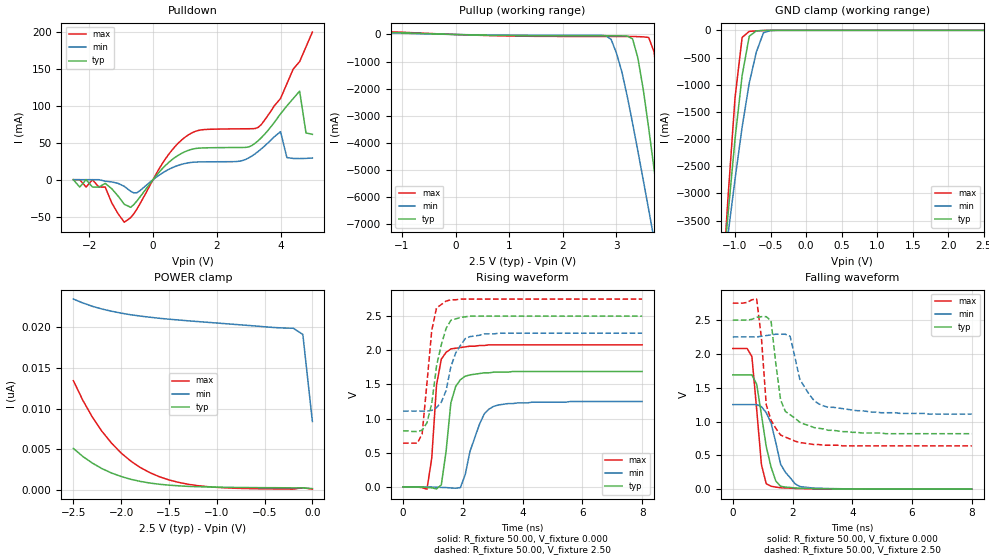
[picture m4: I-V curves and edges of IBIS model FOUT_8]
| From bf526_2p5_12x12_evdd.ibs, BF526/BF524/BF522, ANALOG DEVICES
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|   Model prw0408swcdg_3v_25
[Model]   FOUT_8
Model_type   I/O
Polarity   Non-Inverting
Enable   Active-Low
Vinl =   0.70V
Vinh =   1.70V
Vmeas =   1.20V
Cref =  50.00pF
Rref =   1.00M
Vref =  0.000V
C_comp   4.87pF   4.38pF   5.35pF
[Temperature Range]   25.00   0.12k   -40.00
[Voltage Range]   2.50V   2.25V   2.75V
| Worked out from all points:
|   slope of the pulldown table from 0 to 0.375 V, typ, clamps not added: 20.2 ohm
|   slope of the pullup table from 0 to 0.375 V, typ, clamps not added: 20.2 ohm
|   GND clamp passes 1 mA (typ) near -0.53 V on its own axis
|   rising waveform, R_fixture 50.00, V_fixture 0.000: 20-80 % time 301ps typ, 532ps min, 235ps max; typ from 0 V to 1.69 V
|   rising waveform, R_fixture 50.00, V_fixture 2.50: 20-80 % time 413ps typ, 478ps min, 277ps max; typ from 0.82 V to 2.5 V
|   falling waveform, R_fixture 50.00, V_fixture 0.000: 20-80 % time 405ps typ, 501ps min, 248ps max; typ from 1.69 V to 0 V
|   falling waveform, R_fixture 50.00, V_fixture 2.50: 20-80 % time 392ps typ, 627ps min, 318ps max; typ from 2.5 V to 0.82 V
[Pulldown]
| voltage   I(typ)   I(min)   I(max)
-2.5V     0A         0A         0A
-1.5V     -5mA       -2mA       -10mA
-900mV    -33.4mA    -9mA       -57.6mA
-500mV    -28.54mA   -17.58mA   -39.44mA
1V        37.88mA    21.94mA    57.43mA
3V        44.3mA     29.45mA    69.02mA
3.4V      56.95mA    41.79mA    74.82mA
4V        89.19mA    65.09mA    110mA
4.2V      100mA      29.92mA    130mA
4.6V      120mA      28.6mA     160mA
4.8V      63.36mA    28.84mA    180mA
5V        61.44mA    29.36mA    200mA
[Pullup]
| voltage   I(typ)   I(min)   I(max)
-2.5V     14.15mA    2.47mA     45.09mA
2.8V      -46.96mA   -42.82mA   -72.11mA
2.9V      -47.06mA   -180mA     -72.23mA
3V        -47.56mA   -690mA     -72.33mA
3.3V      -160mA     -3.28A     -74.26mA
3.4V      -880mA     -4.32A     -79.19mA
3.6V      -3.46A     -6.47A     -110mA
3.7V      -4.96A     -7.56A     -640mA
3.8V      -6.5A      -8.65A     -2.2A
4V        -9.62A     -10.85A    -6.34A
4.2V      -12.77A    -13.07A    -10.72A
5V        -25.49A    -21.97A    -28.57A
[GND_clamp]
| voltage   I(typ)   I(min)   I(max)
-2.5V     -25.44A    -19.16A    -34.1A
-1.2V     -4.91A     -4.82A     -5.19A
-1.1V     -3.41A     -3.77A     -3.1A
-1V       -2A        -2.74A     -1.24A
-900mV    -830mA     -1.78A     -130mA
-800mV    -110mA     -970mA     -19.37mA
-700mV    -10.09mA   -400mA     -9.85mA
-600mV    -2.6mA     -44.25mA   -3.52mA
-500mV    -460uA     -4.5mA     -550uA
2.5V      210pA      19.84nA    120pA
[POWER_clamp]
| voltage   I(typ)   I(min)   I(max)
-2.5V     5.13nA     23.39nA    13.41nA
-2.4V     4.13nA     22.91nA    10.99nA
-2.3V     3.32nA     22.5nA     8.93nA
-2.1V     2.11nA     21.9nA     5.76nA
-1.9V     1.35nA     21.47nA    3.58nA
-1.7V     890pA      21.17nA    2.16nA
-1.5V     630pA      20.93nA    1.27nA
-1.2V     440pA      20.64nA    570pA
-800mV    350pA      20.28nA    250pA
-200mV    300pA      19.82nA    150pA
-100mV    300pA      19.07nA    310pA
0V        210pA      8.42nA     140pA
[Ramp]
| variable   typ   min   max
dV/dt_r   1.02/0.30n   0.75/0.50n   1.25/0.19n
dV/dt_f   1.01/0.40n   0.68/0.65n   1.27/0.26n
R_load = 50.00
[Rising Waveform]
R_fixture = 50.00
V_fixture = 0.000
V_fixture_min = 0.000
V_fixture_max = 0.000
L_fixture = 0.000H
C_fixture = 0.000F
| time   V(typ)   V(min)   V(max)
0s        0V         0V         0V
800ps     -9.11mV    -780uV     -33.44mV
960ps     -13.22mV   -2.26mV    420mV
1.12ns    -30.54mV   -4.75mV    1.49V
1.28ns    28.95mV    -7.63mV    1.87V
1.6ns     1.23V      -15.62mV   2.02V
1.92ns    1.57V      -10.23mV   2.04V
2.56ns    1.66V      920mV      2.07V
3.04ns    1.68V      1.18V      2.08V
8ns       1.69V      1.25V      2.08V
[Rising Waveform]
R_fixture = 50.00
V_fixture = 2.50
V_fixture_min = 2.25
V_fixture_max = 2.75
L_fixture = 0.000H
C_fixture = 0.000F
| time   V(typ)   V(min)   V(max)
0s        820mV      1.11V      640mV
480ps     810mV      1.11V      640mV
640ps     830mV      1.11V      780mV
800ps     940mV      1.11V      1.52V
960ps     1.22V      1.12V      2.29V
1.12ns    1.77V      1.16V      2.62V
1.44ns    2.32V      1.41V      2.72V
1.76ns    2.46V      1.96V      2.74V
2.24ns    2.5V       2.2V       2.75V
8ns       2.5V       2.25V      2.75V
[Falling Waveform]
R_fixture = 50.00
V_fixture = 0.000
V_fixture_min = 0.000
V_fixture_max = 0.000
L_fixture = 0.000H
C_fixture = 0.000F
| time   V(typ)   V(min)   V(max)
0s        1.69V      1.25V      2.08V
480ps     1.69V      1.25V      2.08V
640ps     1.69V      1.25V      1.96V
800ps     1.55V      1.25V      1.18V
960ps     1.1V       1.22V      360mV
1.12ns    630mV      1.13V      79.27mV
1.44ns    120mV      690mV      30.31mV
1.6ns     43.21mV    370mV      21.03mV
2.24ns    14.24mV    39.02mV    8.3mV
8ns       42.72uV    120uV      -8.09uV
[Falling Waveform]
R_fixture = 50.00
V_fixture = 2.50
V_fixture_min = 2.25
V_fixture_max = 2.75
L_fixture = 0.000H
C_fixture = 0.000F
| time   V(typ)   V(min)   V(max)
0s        2.5V       2.25V      2.75V
800ps     2.54V      2.25V      2.81V
960ps     2.55V      2.26V      2.23V
1.12ns    2.55V      2.27V      1.25V
1.28ns    2.49V      2.28V      1.02V
1.6ns     1.32V      2.29V      800mV
1.92ns    1.1V       2.26V      740mV
2.24ns    990mV      1.63V      690mV
3.04ns    890mV      1.23V      650mV
8ns       820mV      1.11V      640mV
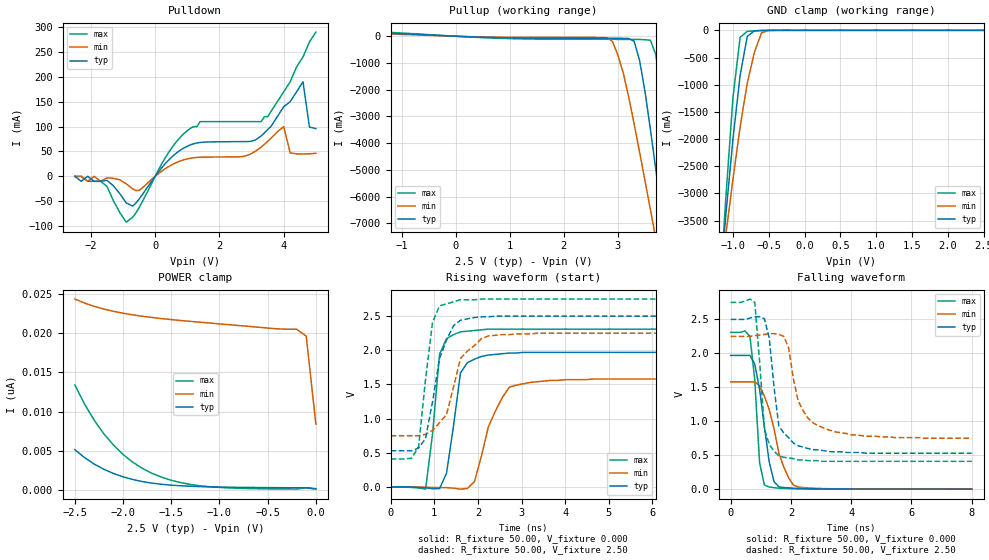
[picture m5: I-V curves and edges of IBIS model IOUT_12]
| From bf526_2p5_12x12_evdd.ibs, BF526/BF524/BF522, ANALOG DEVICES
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|   Model prw0812swcdg_25
[Model]   IOUT_12
Model_type   I/O
Polarity   Non-Inverting
Enable   Active-Low
Vinl =   0.70V
Vinh =   1.70V
Vmeas =   1.20V
Cref =  50.00pF
Rref =   1.00M
Vref =  0.000V
C_comp   4.63pF   4.16pF   5.09pF
[Temperature Range]   25.00   0.12k   -40.00
[Voltage Range]   2.50V   2.25V   2.75V
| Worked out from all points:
|   slope of the pulldown table from 0 to 0.375 V, typ, clamps not added: 12.6 ohm
|   slope of the pullup table from 0 to 0.375 V, typ, clamps not added: 12.7 ohm
|   GND clamp passes 1 mA (typ) near -0.53 V on its own axis
|   rising waveform, R_fixture 50.00, V_fixture 0.000: 20-80 % time 256ps typ, 501ps min, 210ps max; typ from 0 V to 1.97 V
|   rising waveform, R_fixture 50.00, V_fixture 2.50: 20-80 % time 391ps typ, 435ps min, 249ps max; typ from 0.53 V to 2.5 V
|   falling waveform, R_fixture 50.00, V_fixture 0.000: 20-80 % time 369ps typ, 569ps min, 210ps max; typ from 1.97 V to 0 V
|   falling waveform, R_fixture 50.00, V_fixture 2.50: 20-80 % time 302ps typ, 591ps min, 242ps max; typ from 2.5 V to 0.53 V
[Pulldown]
| voltage   I(typ)   I(min)   I(max)
-2.5V     0A         0A         0A
-1.5V     -8mA       -3mA       -20mA
-900mV    -53.4mA    -15mA      -92.2mA
-500mV    -45.67mA   -28.14mA   -63.1mA
900mV     57.24mA    33.39mA    86.24mA
1.4V      68.13mA    38.37mA    110mA
3.3V      81.45mA    59.05mA    110mA
4V        140mA      100mA      170mA
4.2V      150mA      47.04mA    190mA
4.6V      190mA      44.93mA    240mA
4.8V      99.01mA    45.32mA    270mA
5V        95.95mA    46.14mA    290mA
[Pullup]
| voltage   I(typ)   I(min)   I(max)
-2.5V     20.28mA    3.12mA     63.15mA
2.8V      -74.78mA   -59.76mA   -110mA
2.9V      -74.93mA   -200mA     -110mA
3V        -75.48mA   -710mA     -120mA
3.3V      -190mA     -3.29A     -120mA
3.4V      -910mA     -4.34A     -120mA
3.6V      -3.49A     -6.49A     -150mA
3.7V      -4.99A     -7.58A     -690mA
3.8V      -6.53A     -8.67A     -2.24A
4V        -9.65A     -10.87A    -6.38A
4.2V      -12.8A     -13.09A    -10.76A
5V        -25.52A    -21.99A    -28.62A
[GND_clamp]
| voltage   I(typ)   I(min)   I(max)
-2.5V     -25.44A    -19.16A    -34.1A
-1.2V     -4.91A     -4.82A     -5.19A
-1.1V     -3.41A     -3.77A     -3.1A
-1V       -2A        -2.74A     -1.24A
-900mV    -830mA     -1.78A     -130mA
-800mV    -110mA     -970mA     -19.37mA
-700mV    -10.09mA   -400mA     -9.85mA
-600mV    -2.6mA     -44.25mA   -3.52mA
-500mV    -460uA     -4.5mA     -550uA
2.5V      210pA      20.5nA     120pA
[POWER_clamp]
| voltage   I(typ)   I(min)   I(max)
-2.5V     5.16nA     24.33nA    13.41nA
-2.4V     4.16nA     23.83nA    10.99nA
-2.3V     3.34nA     23.41nA    8.94nA
-2.1V     2.14nA     22.77nA    5.76nA
-1.9V     1.37nA     22.32nA    3.58nA
-1.7V     910pA      21.99nA    2.16nA
-1.5V     650pA      21.72nA    1.27nA
-1.2V     460pA      21.38nA    570pA
-800mV    370pA      20.96nA    250pA
-200mV    320pA      20.49nA    150pA
-100mV    320pA      19.61nA    310pA
0V        210pA      8.42nA     140pA
[Ramp]
| variable   typ   min   max
dV/dt_r   1.18/0.27n   0.95/0.49n   1.39/0.18n
dV/dt_f   1.18/0.34n   0.90/0.61n   1.41/0.21n
R_load = 50.00
[Rising Waveform]
R_fixture = 50.00
V_fixture = 0.000
V_fixture_min = 0.000
V_fixture_max = 0.000
L_fixture = 0.000H
C_fixture = 0.000F
| time   V(typ)   V(min)   V(max)
0s        0V         0V         0V
800ps     -11.89mV   -3.81mV    -32.05mV
960ps     -26.13mV   -8.01mV    780mV
1.12ns    -25.26mV   -9.46mV    1.94V
1.28ns    200mV      -10.41mV   2.17V
1.44ns    890mV      -17.4mV    2.23V
1.6ns     1.67V      -32.46mV   2.27V
1.76ns    1.82V      -20.89mV   2.28V
2.72ns    1.96V      1.46V      2.31V
8ns       1.97V      1.58V      2.31V
[Rising Waveform]
R_fixture = 50.00
V_fixture = 2.50
V_fixture_min = 2.25
V_fixture_max = 2.75
L_fixture = 0.000H
C_fixture = 0.000F
| time   V(typ)   V(min)   V(max)
0s        530mV      750mV      410mV
480ps     530mV      750mV      420mV
640ps     570mV      750mV      590mV
800ps     710mV      770mV      1.58V
960ps     1.25V      830mV      2.41V
1.12ns    1.88V      940mV      2.65V
1.28ns    2.15V      1.06V      2.68V
1.6ns     2.44V      1.88V      2.74V
2.24ns    2.49V      2.21V      2.75V
8ns       2.5V       2.25V      2.75V
[Falling Waveform]
R_fixture = 50.00
V_fixture = 0.000
V_fixture_min = 0.000
V_fixture_max = 0.000
L_fixture = 0.000H
C_fixture = 0.000F
| time   V(typ)   V(min)   V(max)
0s        1.97V      1.58V      2.31V
640ps     1.97V      1.58V      2.25V
800ps     1.84V      1.58V      1.61V
960ps     1.47V      1.52V      390mV
1.12ns    920mV      1.37V      62.08mV
1.28ns    400mV      1.17V      32.11mV
1.44ns    110mV      890mV      21.89mV
1.6ns     34.88mV    530mV      14.19mV
2.08ns    14.16mV    61.44mV    7.36mV
8ns       13.11uV    60.2uV     13.29uV
[Falling Waveform]
R_fixture = 50.00
V_fixture = 2.50
V_fixture_min = 2.25
V_fixture_max = 2.75
L_fixture = 0.000H
C_fixture = 0.000F
| time   V(typ)   V(min)   V(max)
0s        2.5V       2.25V      2.75V
800ps     2.54V      2.26V      2.75V
1.12ns    2.51V      2.28V      890mV
1.28ns    2.23V      2.29V      660mV
1.6ns     930mV      2.28V      490mV
1.92ns    760mV      2.09V      460mV
2.24ns    640mV      1.3V       430mV
2.88ns    580mV      940mV      420mV
4.48ns    530mV      780mV      410mV
8ns       530mV      750mV      410mV
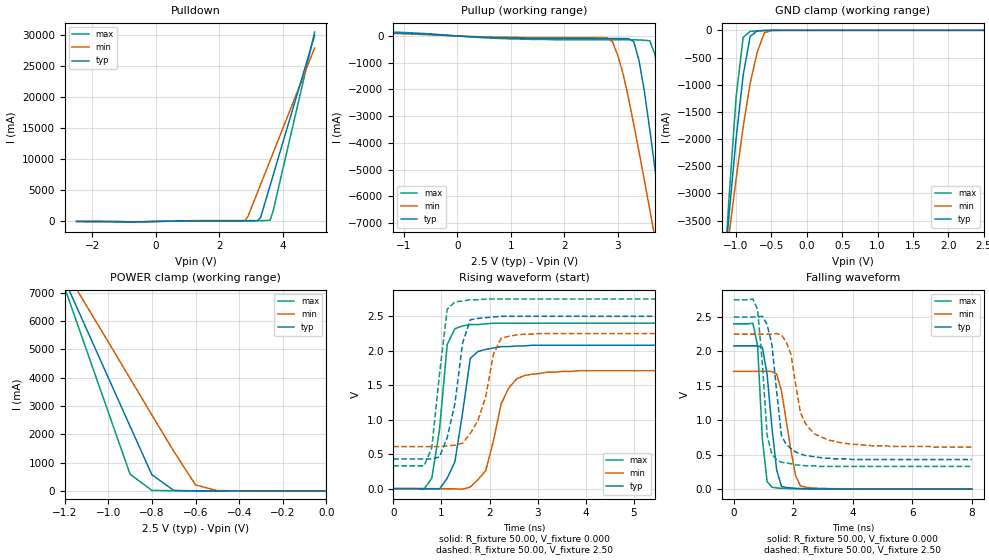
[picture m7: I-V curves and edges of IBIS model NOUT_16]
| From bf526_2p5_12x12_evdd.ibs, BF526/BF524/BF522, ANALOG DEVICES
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|   Model prw1216hcdg_25
[Model]   NOUT_16
Model_type   I/O
Polarity   Non-Inverting
Enable   Active-Low
Vinl =   0.70V
Vinh =   1.70V
Vmeas =   1.20V
Cref =  50.00pF
Rref =   1.00M
Vref =  0.000V
C_comp   4.85pF   4.37pF   5.34pF
[Temperature Range]   25.00   0.12k   -40.00
[Voltage Range]   2.50V   2.25V   2.75V
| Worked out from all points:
|   slope of the pulldown table from 0 to 0.375 V, typ, clamps not added: 10.1 ohm
|   slope of the pullup table from 0 to 0.375 V, typ, clamps not added: 9.95 ohm
|   GND clamp passes 1 mA (typ) near -0.53 V on its own axis
|   POWER clamp passes 1 mA (typ) near -0.53 V on its own axis
|   rising waveform, R_fixture 50.00, V_fixture 0.000: 20-80 % time 268ps typ, 385ps min, 223ps max; typ from 0 V to 2.08 V
|   rising waveform, R_fixture 50.00, V_fixture 2.50: 20-80 % time 282ps typ, 357ps min, 230ps max; typ from 0.43 V to 2.5 V
|   falling waveform, R_fixture 50.00, V_fixture 0.000: 20-80 % time 286ps typ, 391ps min, 206ps max; typ from 2.08 V to 0 V
|   falling waveform, R_fixture 50.00, V_fixture 2.50: 20-80 % time 301ps typ, 505ps min, 245ps max; typ from 2.5 V to 0.43 V
[Pulldown]
| voltage   I(typ)   I(min)   I(max)
-2.5V     0A         0A         0A
-900mV    -66.7mA    -19mA      -120mA
900mV     71.55mA    41.73mA    110mA
2.8V      87.33mA    98.46mA    140mA
2.9V      87.43mA    800mA      140mA
3.2V      100mA      4.66A      140mA
3.3V      650mA      5.95A      140mA
3.6V      5.81A      9.81A      200mA
3.7V      7.53A      11.1A      1.82A
5V        29.92A     27.88A     30.44A
[Pullup]
| voltage   I(typ)   I(min)   I(max)
-2.5V     190mA      170mA      220mA
2.8V      -94.19mA   -73.06mA   -140mA
2.9V      -94.42mA   -210mA     -140mA
3V        -95.02mA   -720mA     -140mA
3.3V      -210mA     -3.31A     -140mA
3.4V      -930mA     -4.35A     -150mA
3.6V      -3.51A     -6.5A      -180mA
3.7V      -5.01A     -7.59A     -710mA
3.8V      -6.55A     -8.69A     -2.27A
4V        -9.67A     -10.89A    -6.41A
4.2V      -12.82A    -13.1A     -10.79A
5V        -25.54A    -22A       -28.64A
[GND_clamp]
| voltage   I(typ)   I(min)   I(max)
-2.5V     -25.44A    -19.16A    -34.1A
-1.2V     -4.91A     -4.82A     -5.19A
-1.1V     -3.41A     -3.77A     -3.1A
-1V       -2A        -2.74A     -1.24A
-900mV    -830mA     -1.78A     -130mA
-800mV    -110mA     -970mA     -19.32mA
-700mV    -10.06mA   -400mA     -9.82mA
-600mV    -2.59mA    -44.2mA    -3.51mA
-500mV    -470uA     -4.47mA    -560uA
2.5V      200pA      14.35uA    -5.72uA
[POWER_clamp]
| voltage   I(typ)   I(min)   I(max)
-2.5V     29.82A     24.6A      35.79A
-1.2V     7.44A      7.83A      7.18A
-1.1V     5.72A      6.54A      4.98A
-900mV    2.28A      3.97A      590mA
-800mV    570mA      2.68A      17.01mA
-700mV    17.04mA    1.4A       7.09mA
-600mV    2.37mA     210mA      2.78mA
-500mV    470uA      11.87mA    550uA
0V        200pA      8.28nA     120pA
[Ramp]
| variable   typ   min   max
dV/dt_r   1.25/0.27n   1.03/0.41n   1.44/0.18n
dV/dt_f   1.24/0.31n   0.98/0.52n   1.45/0.22n
R_load = 50.00
[Rising Waveform]
R_fixture = 50.00
V_fixture = 0.000
V_fixture_min = 0.000
V_fixture_max = 0.000
L_fixture = 0.000H
C_fixture = 0.000F
| time   V(typ)   V(min)   V(max)
0s        0V         0V         0V
800ps     -3.84mV    -200uV     150mV
960ps     -5.36mV    -850uV     850mV
1.12ns    150mV      -1.76mV    2.09V
1.28ns    390mV      -3.49mV    2.32V
1.6ns     1.89V      23.39mV    2.38V
1.76ns    1.99V      130mV      2.38V
2.24ns    2.06V      1.23V      2.4V
2.72ns    2.07V      1.64V      2.4V
8ns       2.08V      1.71V      2.4V
[Rising Waveform]
R_fixture = 50.00
V_fixture = 2.50
V_fixture_min = 2.25
V_fixture_max = 2.75
L_fixture = 0.000H
C_fixture = 0.000F
| time   V(typ)   V(min)   V(max)
0s        430mV      610mV      330mV
640ps     430mV      610mV      330mV
800ps     430mV      610mV      590mV
1.12ns    740mV      620mV      2.6V
1.28ns    1.23V      630mV      2.71V
1.44ns    2.11V      660mV      2.72V
1.6ns     2.45V      800mV      2.74V
1.92ns    2.48V      1.33V      2.75V
2.24ns    2.5V       2.18V      2.75V
8ns       2.5V       2.25V      2.75V
[Falling Waveform]
R_fixture = 50.00
V_fixture = 0.000
V_fixture_min = 0.000
V_fixture_max = 0.000
L_fixture = 0.000H
C_fixture = 0.000F
| time   V(typ)   V(min)   V(max)
0s        2.08V      1.71V      2.4V
640ps     2.08V      1.71V      2.41V
800ps     2.08V      1.71V      2.08V
960ps     2.06V      1.71V      730mV
1.12ns    1.66V      1.71V      110mV
1.28ns    900mV      1.71V      29.76mV
1.6ns     40.29mV    1.43V      12mV
2.08ns    12.44mV    190mV      5.89mV
2.24ns    9.64mV     48.42mV    4.39mV
8ns       54.63uV    120uV      17.4uV
[Falling Waveform]
R_fixture = 50.00
V_fixture = 2.50
V_fixture_min = 2.25
V_fixture_max = 2.75
L_fixture = 0.000H
C_fixture = 0.000F
| time   V(typ)   V(min)   V(max)
0s        2.5V       2.25V      2.75V
800ps     2.5V       2.25V      2.61V
1.12ns    2.39V      2.25V      780mV
1.28ns    2.1V       2.25V      510mV
1.44ns    1.42V      2.26V      430mV
1.6ns     780mV      2.24V      390mV
1.76ns    650mV      2.14V      380mV
2.24ns    510mV      1.11V      350mV
2.72ns    470mV      800mV      340mV
8ns       430mV      610mV      330mV
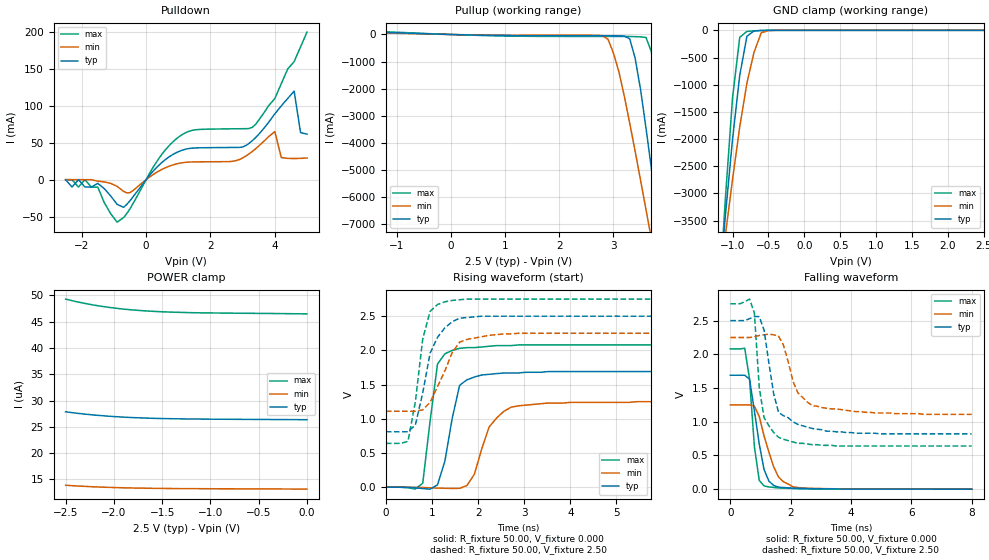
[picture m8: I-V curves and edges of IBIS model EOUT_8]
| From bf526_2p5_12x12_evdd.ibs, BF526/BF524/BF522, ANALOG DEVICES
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|   Model prwd0408swcdg_25
[Model]   EOUT_8
Model_type   I/O
Polarity   Non-Inverting
Enable   Active-Low
Vinl =   0.70V
Vinh =   1.70V
Vmeas =   1.20V
Cref =  50.00pF
Rref =   1.00M
Vref =  0.000V
C_comp   4.85pF   4.37pF   5.34pF
[Temperature Range]   25.00   0.12k   -40.00
[Voltage Range]   2.50V   2.25V   2.75V
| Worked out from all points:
|   slope of the pulldown table from 0 to 0.375 V, typ, clamps not added: 20.2 ohm
|   slope of the pullup table from 0 to 0.375 V, typ, clamps not added: 20.2 ohm
|   GND clamp passes 1 mA (typ) near -0.52 V on its own axis
|   rising waveform, R_fixture 50.00, V_fixture 0.000: 20-80 % time 293ps typ, 442ps min, 231ps max; typ from 0 V to 1.69 V
|   rising waveform, R_fixture 50.00, V_fixture 2.50: 20-80 % time 380ps typ, 467ps min, 275ps max; typ from 0.81 V to 2.5 V
|   falling waveform, R_fixture 50.00, V_fixture 0.000: 20-80 % time 365ps typ, 521ps min, 240ps max; typ from 1.69 V to 0 V
|   falling waveform, R_fixture 50.00, V_fixture 2.50: 20-80 % time 407ps typ, 615ps min, 278ps max; typ from 2.5 V to 0.82 V
[Pulldown]
| voltage   I(typ)   I(min)   I(max)
-2.5V     0A         0A         0A
-1.5V     -5mA       -2mA       -10mA
-900mV    -33.4mA    -9mA       -57.6mA
-500mV    -28.54mA   -17.58mA   -39.44mA
1V        37.88mA    21.95mA    57.44mA
3V        44.32mA    29.46mA    69.07mA
3.4V      56.97mA    41.8mA     74.87mA
4V        89.22mA    65.19mA    110mA
4.2V      100mA      30.03mA    130mA
4.6V      120mA      28.65mA    160mA
4.8V      63.75mA    28.88mA    180mA
5V        61.71mA    29.4mA     200mA
[Pullup]
| voltage   I(typ)   I(min)   I(max)
-2.5V     14.41mA    2.51mA     46.6mA
2.8V      -46.97mA   -42.82mA   -72.12mA
2.9V      -47.08mA   -180mA     -72.23mA
3V        -47.58mA   -690mA     -72.35mA
3.3V      -160mA     -3.28A     -74.28mA
3.4V      -880mA     -4.32A     -79.2mA
3.6V      -3.46A     -6.47A     -110mA
3.7V      -4.96A     -7.56A     -640mA
3.8V      -6.5A      -8.65A     -2.2A
4V        -9.62A     -10.85A    -6.34A
4.2V      -12.77A    -13.07A    -10.72A
5V        -25.49A    -21.97A    -28.57A
[GND_clamp]
| voltage   I(typ)   I(min)   I(max)
-2.5V     -25.44A    -19.16A    -34.1A
-1.2V     -4.91A     -4.82A     -5.19A
-1.1V     -3.41A     -3.77A     -3.1A
-1V       -2A        -2.74A     -1.24A
-900mV    -830mA     -1.78A     -130mA
-800mV    -110mA     -970mA     -19.39mA
-700mV    -10.1mA    -400mA     -9.87mA
-600mV    -2.61mA    -44.25mA   -3.54mA
-500mV    -470uA     -4.51mA    -570uA
2.5V      26.35uA    13.17uA    46.42uA
[POWER_clamp]
| voltage   I(typ)   I(min)   I(max)
-2.5V     27.85uA    13.87uA    49.31uA
-2.4V     27.62uA    13.76uA    48.86uA
-2.3V     27.41uA    13.66uA    48.48uA
-2.2V     27.23uA    13.57uA    48.14uA
-2.1V     27.08uA    13.5uA     47.85uA
-1.9V     26.84uA    13.39uA    47.4uA
-1.7V     26.68uA    13.32uA    47.09uA
-1.5V     26.57uA    13.27uA    46.89uA
-1.2V     26.48uA    13.23uA    46.72uA
-700mV    26.42uA    13.19uA    46.61uA
-400mV    26.39uA    13.18uA    46.57uA
0V        26.35uA    13.13uA    46.49uA
[Ramp]
| variable   typ   min   max
dV/dt_r   1.02/0.29n   0.75/0.48n   1.25/0.19n
dV/dt_f   1.01/0.42n   0.68/0.64n   1.27/0.27n
R_load = 50.00
[Rising Waveform]
R_fixture = 50.00
V_fixture = 0.000
V_fixture_min = 0.000
V_fixture_max = 0.000
L_fixture = 0.000H
C_fixture = 0.000F
| time   V(typ)   V(min)   V(max)
0s        0V         0V         0V
800ps     -19.63mV   -4.22mV    58.47mV
1.12ns    34.5mV     -13.25mV   1.8V
1.28ns    380mV      -16.02mV   1.95V
1.44ns    1.01V      -18.8mV    2V
1.6ns     1.49V      -17.69mV   2.03V
1.92ns    1.61V      190mV      2.04V
2.24ns    1.65V      880mV      2.06V
2.72ns    1.67V      1.17V      2.07V
8ns       1.69V      1.25V      2.08V
[Rising Waveform]
R_fixture = 50.00
V_fixture = 2.50
V_fixture_min = 2.25
V_fixture_max = 2.75
L_fixture = 0.000H
C_fixture = 0.000F
| time   V(typ)   V(min)   V(max)
0s        810mV      1.11V      640mV
480ps     810mV      1.11V      670mV
640ps     910mV      1.11V      1.25V
800ps     1.38V      1.13V      2.17V
960ps     1.96V      1.24V      2.57V
1.12ns    2.19V      1.47V      2.67V
1.44ns    2.42V      1.97V      2.73V
1.6ns     2.47V      2.12V      2.74V
2.24ns    2.5V       2.22V      2.75V
8ns       2.5V       2.25V      2.75V
[Falling Waveform]
R_fixture = 50.00
V_fixture = 0.000
V_fixture_min = 0.000
V_fixture_max = 0.000
L_fixture = 0.000H
C_fixture = 0.000F
| time   V(typ)   V(min)   V(max)
0s        1.69V      1.25V      2.08V
480ps     1.69V      1.25V      2.09V
640ps     1.63V      1.25V      1.63V
800ps     1.16V      1.23V      630mV
960ps     670mV      1.08V      130mV
1.12ns    290mV      790mV      48.33mV
1.28ns    120mV      550mV      33.1mV
1.6ns     30.42mV    180mV      17.25mV
2.08ns    15.26mV    35.73mV    9.55mV
8ns       52.52uV    76.44uV    31.29uV
[Falling Waveform]
R_fixture = 50.00
V_fixture = 2.50
V_fixture_min = 2.25
V_fixture_max = 2.75
L_fixture = 0.000H
C_fixture = 0.000F
| time   V(typ)   V(min)   V(max)
0s        2.5V       2.25V      2.75V
640ps     2.53V      2.25V      2.82V
800ps     2.56V      2.26V      2.61V
960ps     2.56V      2.28V      1.51V
1.12ns    2.36V      2.29V      1.06V
1.44ns    1.41V      2.29V      840mV
1.6ns     1.14V      2.27V      770mV
2.24ns    960mV      1.43V      680mV
2.72ns    900mV      1.24V      660mV
8ns       820mV      1.11V      640mV
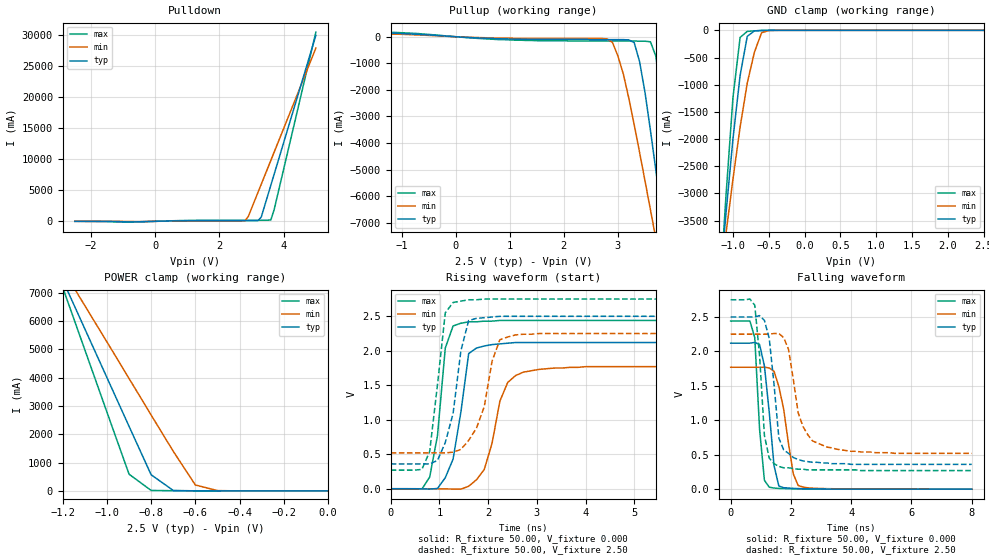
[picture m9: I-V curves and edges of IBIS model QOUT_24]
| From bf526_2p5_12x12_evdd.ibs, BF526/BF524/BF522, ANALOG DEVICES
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|   Model prw1624cdg_25
[Model]   QOUT_24
Model_type   I/O
Polarity   Non-Inverting
Enable   Active-Low
Vinl =   0.70V
Vinh =   1.70V
Vmeas =   1.20V
Cref =  50.00pF
Rref =   1.00M
Vref =  0.000V
C_comp   4.85pF   4.37pF   5.34pF
[Temperature Range]   25.00   0.12k   -40.00
[Voltage Range]   2.50V   2.25V   2.75V
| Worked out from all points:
|   slope of the pulldown table from 0 to 0.375 V, typ, clamps not added: 8.41 ohm
|   slope of the pullup table from 0 to 0.375 V, typ, clamps not added: 8.85 ohm
|   GND clamp passes 1 mA (typ) near -0.53 V on its own axis
|   POWER clamp passes 1 mA (typ) near -0.53 V on its own axis
|   rising waveform, R_fixture 50.00, V_fixture 0.000: 20-80 % time 274ps typ, 375ps min, 224ps max; typ from 0 V to 2.12 V
|   rising waveform, R_fixture 50.00, V_fixture 2.50: 20-80 % time 301ps typ, 360ps min, 237ps max; typ from 0.36 V to 2.5 V
|   falling waveform, R_fixture 50.00, V_fixture 0.000: 20-80 % time 280ps typ, 395ps min, 213ps max; typ from 2.12 V to 0 V
|   falling waveform, R_fixture 50.00, V_fixture 2.50: 20-80 % time 282ps typ, 493ps min, 236ps max; typ from 2.5 V to 0.36 V
[Pulldown]
| voltage   I(typ)   I(min)   I(max)
-2.5V     0A         0A         0A
-900mV    -80.1mA    -23mA      -140mA
1.1V      95.08mA    54.68mA    150mA
2.8V      100mA      110mA      170mA
2.9V      100mA      810mA      170mA
3.2V      120mA      4.67A      170mA
3.3V      670mA      5.96A      170mA
3.6V      5.83A      9.82A      230mA
3.7V      7.55A      11.11A     1.85A
5V        29.94A     27.89A     30.47A
[Pullup]
| voltage   I(typ)   I(min)   I(max)
-2.5V     220mA      190mA      250mA
2.8V      -110mA     -80.42mA   -160mA
2.9V      -110mA     -220mA     -160mA
3V        -110mA     -730mA     -160mA
3.3V      -220mA     -3.31A     -160mA
3.4V      -940mA     -4.36A     -170mA
3.6V      -3.52A     -6.51A     -190mA
3.7V      -5.02A     -7.6A      -730mA
3.8V      -6.56A     -8.69A     -2.28A
4V        -9.68A     -10.89A    -6.43A
4.2V      -12.83A    -13.11A    -10.8A
5V        -25.55A    -22.01A    -28.66A
[GND_clamp]
| voltage   I(typ)   I(min)   I(max)
-2.5V     -25.44A    -19.16A    -34.1A
-1.2V     -4.91A     -4.82A     -5.19A
-1.1V     -3.41A     -3.77A     -3.1A
-1V       -2A        -2.74A     -1.24A
-900mV    -830mA     -1.78A     -130mA
-800mV    -110mA     -970mA     -19.31mA
-700mV    -10.05mA   -400mA     -9.81mA
-600mV    -2.58mA    -44.19mA   -3.5mA
-500mV    -450uA     -4.46mA    -550uA
2.5V      190pA      11.03uA    100pA
[POWER_clamp]
| voltage   I(typ)   I(min)   I(max)
-2.5V     29.82A     24.6A      35.79A
-1.2V     7.44A      7.83A      7.18A
-1.1V     5.72A      6.54A      4.98A
-900mV    2.28A      3.97A      590mA
-800mV    570mA      2.68A      16.99mA
-700mV    17.03mA    1.4A       7.08mA
-600mV    2.36mA     210mA      2.77mA
-500mV    460uA      11.86mA    530uA
0V        190pA      8.27nA     120pA
[Ramp]
| variable   typ   min   max
dV/dt_r   1.27/0.28n   1.06/0.40n   1.46/0.20n
dV/dt_f   1.29/0.30n   1.04/0.50n   1.49/0.21n
R_load = 50.00
[Rising Waveform]
R_fixture = 50.00
V_fixture = 0.000
V_fixture_min = 0.000
V_fixture_max = 0.000
L_fixture = 0.000H
C_fixture = 0.000F
| time   V(typ)   V(min)   V(max)
0s        0V         0V         0V
800ps     -5.06mV    -310uV     170mV
960ps     3.91mV     -1.06mV    770mV
1.12ns    160mV      -2.22mV    2.04V
1.28ns    430mV      -4.53mV    2.36V
1.6ns     1.96V      36.24mV    2.42V
1.76ns    2.04V      130mV      2.42V
2.4ns     2.11V      1.54V      2.44V
2.72ns    2.12V      1.69V      2.44V
8ns       2.12V      1.77V      2.44V
[Rising Waveform]
R_fixture = 50.00
V_fixture = 2.50
V_fixture_min = 2.25
V_fixture_max = 2.75
L_fixture = 0.000H
C_fixture = 0.000F
| time   V(typ)   V(min)   V(max)
0s        360mV      520mV      270mV
640ps     360mV      520mV      280mV
800ps     360mV      520mV      540mV
1.12ns    670mV      520mV      2.55V
1.28ns    1.09V      530mV      2.7V
1.44ns    2V         570mV      2.72V
1.6ns     2.44V      700mV      2.74V
1.92ns    2.48V      1.19V      2.75V
2.24ns    2.5V       2.16V      2.75V
8ns       2.5V       2.25V      2.75V
[Falling Waveform]
R_fixture = 50.00
V_fixture = 0.000
V_fixture_min = 0.000
V_fixture_max = 0.000
L_fixture = 0.000H
C_fixture = 0.000F
| time   V(typ)   V(min)   V(max)
0s        2.12V      1.77V      2.44V
800ps     2.13V      1.77V      2.2V
960ps     2.1V       1.77V      870mV
1.12ns    1.79V      1.77V      130mV
1.28ns    1.12V      1.76V      28.37mV
1.44ns    340mV      1.71V      16.33mV
1.6ns     45.27mV    1.49V      10.87mV
2.08ns    11.64mV    220mV      4.89mV
2.24ns    8.42mV     53.28mV    3.74mV
8ns       11.91uV    62.12uV    -450nV
[Falling Waveform]
R_fixture = 50.00
V_fixture = 2.50
V_fixture_min = 2.25
V_fixture_max = 2.75
L_fixture = 0.000H
C_fixture = 0.000F
| time   V(typ)   V(min)   V(max)
0s        2.5V       2.25V      2.75V
800ps     2.5V       2.25V      2.67V
960ps     2.52V      2.25V      1.94V
1.12ns    2.45V      2.25V      780mV
1.44ns    1.52V      2.26V      370mV
1.6ns     740mV      2.26V      330mV
1.76ns    570mV      2.2V       310mV
2.24ns    430mV      1.11V      290mV
2.72ns    390mV      700mV      280mV
8ns       360mV      520mV      270mV
